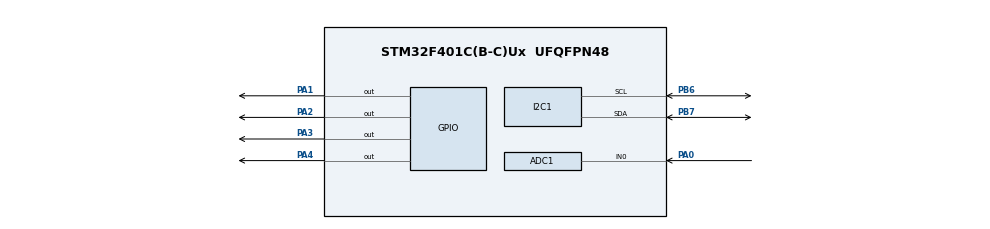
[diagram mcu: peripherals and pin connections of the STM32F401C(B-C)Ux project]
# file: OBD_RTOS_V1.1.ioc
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ADC1.Channel-0\#ChannelRegularConversion=ADC_CHANNEL_0
ADC1.NbrOfConversionFlag=1
ADC1.Rank-0\#ChannelRegularConversion=1
ADC1.SamplingTime-0\#ChannelRegularConversion=ADC_SAMPLETIME_3CYCLES
ADC1.master=1
FREERTOS.Tasks01=Tim_Task1,24,128,IncTimFunc,Default,NULL,Dynamic,NULL,NULL;TimTask2,8,128,EEPROM_saveTimVal,Default,NULL,Dynamic,NULL,NULL;fuelLevelTask1,8,128,getFuelLevelFromADC,Default,NULL,Dynamic,NULL,NULL;fuelLevelTask2,8,128,mapFuelLevelDigtalToLED,Default,NULL,Dynamic,NULL,NULL
Mcu.Family=STM32F4
Mcu.Name=STM32F401C(B-C)Ux
Mcu.Package=UFQFPN48
NVIC.PriorityGroup=NVIC_PRIORITYGROUP_4
PA0-WKUP.Signal=ADCx_IN0
PA1.Signal=GPIO_Output
PA2.Signal=GPIO_Output
PA3.Signal=GPIO_Output
PA4.Signal=GPIO_Output
PB6.Mode=I2C
PB6.Signal=I2C1_SCL
PB7.Mode=I2C
PB7.Signal=I2C1_SDA
ProjectManager.HeapSize=0x200
ProjectManager.StackSize=0x400
ProjectManager.TargetToolchain=STM32CubeIDE
RCC.48MHZClocksFreq_Value=36000000
RCC.AHBFreq_Value=72000000
RCC.APB1CLKDivider=RCC_HCLK_DIV2
RCC.APB1Freq_Value=36000000
RCC.APB1TimFreq_Value=72000000
RCC.APB2Freq_Value=72000000
RCC.APB2TimFreq_Value=72000000
RCC.CortexFreq_Value=72000000
RCC.HCLKFreq_Value=72000000
RCC.HSE_VALUE=25000000
RCC.HSI_VALUE=16000000
RCC.LSE_VALUE=32768
RCC.PLLM=8
RCC.PLLN=72
RCC.SYSCLKFreq_VALUE=72000000
RCC.SYSCLKSource=RCC_SYSCLKSOURCE_PLLCLK
RCC.VCOOutputFreq_Value=144000000
SH.ADCx_IN0.0=ADC1_IN0,IN0
VP_FREERTOS_VS_CMSIS_V2.Mode=CMSIS_V2
board=custom

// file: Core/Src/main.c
/* USER CODE BEGIN Header */
/**
 ******************************************************************************
 * @file           : main.c
 * @brief          : Main program body
 ******************************************************************************
 * @attention
 *
 * Copyright (c) 2023 STMicroelectronics.
 * All rights reserved.
 *
 * This software is licensed under terms that can be found in the LICENSE file
 * in the root directory of this software component.
 * If no LICENSE file comes with this software, it is provided AS-IS.
 *
 ******************************************************************************
 */
/* USER CODE END Header */
#include "main.h"
#include "cmsis_os.h"

/* USER CODE BEGIN Includes */
#include "EEPROM.h"
/* USER CODE END Includes */

/* USER CODE BEGIN PD */

//timer and eeprom
#define PAGE_NUM_TIM_LOC        1
#define PAGE_NUM_FLAG_LOC       100

#define OFFSET_NUM_TIM          1
#define OFFSET_NUM_FLAG         3

#define TIM_SIZE_DATA           4
#define FLAG_SIZE_DATA          1

#define FIRST_TIME             0xFF

//ADC and fuel level
#define FUEL_SENSOR_PIN				GPIO_PIN_0
#define FUEL_SENSOR_PORT			GPIOA

#define FUEL_LED0_PIN				GPIO_PIN_1
#define FUEL_LED0_PORT				GPIOA

#define FUEL_LED1_PIN				GPIO_PIN_2
#define FUEL_LED1_PORT				GPIOA

#define FUEL_LED2_PIN				GPIO_PIN_3
#define FUEL_LED2_PORT				GPIOA

#define FUEL_LED3_PIN				GPIO_PIN_4
#define FUEL_LED3_PORT				GPIOA

#define FUEL_MAX_DIGITA_VALUE		4096
#define FUEL_MINIMUM_DIGITA_VALUE	0

#define FUEL_LEVEL_FULL_TANK		4
#define FUEL_LEVEL_THREE_Q_TANK		3
#define FUEL_LEVEL_HALF_TANK		2
#define FUEL_LEVEL_QUARTER_TANK		1
#define FUEL_LEVEL_EMPTY_TANK		0
//lm35 temprature part
#define LM35_SENSOR_PIN				GPIO_PIN_5
#define LM35_SENSOR_PORT			GPIOA

#define LM35_MAX_DIGITA_VALUE		4096
#define LM35_MINIMUM_DIGITA_VALUE	0

#define LM35_MAX_TEMPRATURE			150
#define LM35_MINIMUM_TEMPRATURE		2

#define LM35_MAX_OUT_VOLt			1480 	//in mv
#define LM35_MINIMUM_OUT_VOLT		0

/* USER CODE END PD */

ADC_HandleTypeDef hadc1;

I2C_HandleTypeDef hi2c1;

/* Definitions for tim_Task1 */
osThreadId_t tim_Task1Handle;
const osThreadAttr_t tim_Task1_attributes = {
		.name = "tim_Task1",
		.stack_size = 128 * 4,
		.priority = (osPriority_t) osPriorityNormal,
};
/* Definitions for timTask2 */
osThreadId_t timTask2Handle;
const osThreadAttr_t timTask2_attributes = {
		.name = "timTask2",
		.stack_size = 128 * 4,
		.priority = (osPriority_t) osPriorityLow,
};
/* Definitions for fuelLevelTask1 */
osThreadId_t fuelLevelTask1Handle;
const osThreadAttr_t fuelLevelTask1_attributes = {
		.name = "fuelLevelTask1",
		.stack_size = 128 * 4,
		.priority = (osPriority_t) osPriorityLow,
};
/* Definitions for fuelLevelTask2 */
osThreadId_t fuelLevelTask2Handle;
const osThreadAttr_t fuelLevelTask2_attributes = {
		.name = "fuelLevelTask2",
		.stack_size = 128 * 4,
		.priority = (osPriority_t) osPriorityLow,
};
/* Definitions for LM35Task0 */
osThreadId_t LM35Task0Handle;
const osThreadAttr_t LM35Task0_attributes = {
		.name = "LM35Task0",
		.stack_size = 128 * 4,
		.priority = (osPriority_t) osPriorityLow,
};
/* USER CODE BEGIN PV */

//time and eeprom
uint32_t g_timeElapsedSec = 0;
uint8_t g_flag ;
uint8_t Done = 0x2;

// fuel level
uint32_t adcFuelValue ;
uint8_t curretFuelValue ;

// lm35 temprature
uint16_t ADC_TempratureDigitalRead ;
uint8_t  temperatureInCelsius ;
uint16_t  temperatureInMVolt ;

/* USER CODE END PV */

void SystemClock_Config(void);
static void MX_GPIO_Init(void);
static void MX_I2C1_Init(void);
static void MX_ADC1_Init(void);
void IncTimFunc(void *argument);
void EEPROM_saveTimVal(void *argument);
void getFuelLevelFromADC(void *argument);
void mapFuelLevelDigtalToLED(void *argument);
void LM35_getTemprature(void *argument);

/* USER CODE BEGIN PFP */

//time and eeprom
void EEPROM_voidInitTime(void);
uint32_t GetElapsedTime(void);

//fuel level
void mapDigitalvalueToLeds(uint32_t digitalValue);

//lm35 temprature

void getDigitalTemperatureFromADC ();
void mapDigitalTemperatureToVolt();
void mapMVoltToCelsius();

/* USER CODE END PFP */

int main(void)
{

	/* MCU Configuration--------------------------------------------------------*/

	/* Reset of all peripherals, Initializes the Flash interface and the Systick. */
	HAL_Init();

	/* Configure the system clock */
	SystemClock_Config();

	/* Initialize all configured peripherals */
	MX_GPIO_Init();
	MX_I2C1_Init();
	MX_ADC1_Init();
	/* USER CODE BEGIN 2 */
	HAL_I2C_Init(&hi2c1);
	EEPROM_voidInitTime();

	/* USER CODE END 2 */

	/* Init scheduler */
	osKernelInitialize();

	/* Create the thread(s) */
	/* creation of tim_Task1 */
	tim_Task1Handle = osThreadNew(IncTimFunc, NULL, &tim_Task1_attributes);

	/* creation of timTask2 */
	timTask2Handle = osThreadNew(EEPROM_saveTimVal, NULL, &timTask2_attributes);

	/* creation of fuelLevelTask1 */
	fuelLevelTask1Handle = osThreadNew(getFuelLevelFromADC, NULL, &fuelLevelTask1_attributes);

	/* creation of fuelLevelTask2 */
	fuelLevelTask2Handle = osThreadNew(mapFuelLevelDigtalToLED, NULL, &fuelLevelTask2_attributes);

	/* creation of LM35Task0 */
	LM35Task0Handle = osThreadNew(LM35_getTemprature, NULL, &LM35Task0_attributes);

	/* Start scheduler */
	osKernelStart();

	/* We should never get here as control is now taken by the scheduler */
	/* Infinite loop */
	while (1)
	{

	}
}

void SystemClock_Config(void)
{
	RCC_OscInitTypeDef RCC_OscInitStruct = {0};
	RCC_ClkInitTypeDef RCC_ClkInitStruct = {0};

	/** Configure the main internal regulator output voltage
	 */
	__HAL_RCC_PWR_CLK_ENABLE();
	__HAL_PWR_VOLTAGESCALING_CONFIG(PWR_REGULATOR_VOLTAGE_SCALE2);

	/** Initializes the RCC Oscillators according to the specified parameters
	 * in the RCC_OscInitTypeDef structure.
	 */
	RCC_OscInitStruct.OscillatorType = RCC_OSCILLATORTYPE_HSI;
	RCC_OscInitStruct.HSIState = RCC_HSI_ON;
	RCC_OscInitStruct.HSICalibrationValue = RCC_HSICALIBRATION_DEFAULT;
	RCC_OscInitStruct.PLL.PLLState = RCC_PLL_NONE;
	if (HAL_RCC_OscConfig(&RCC_OscInitStruct) != HAL_OK)
	{
		Error_Handler();
	}

	/** Initializes the CPU, AHB and APB buses clocks
	 */
	RCC_ClkInitStruct.ClockType = RCC_CLOCKTYPE_HCLK|RCC_CLOCKTYPE_SYSCLK
			|RCC_CLOCKTYPE_PCLK1|RCC_CLOCKTYPE_PCLK2;
	RCC_ClkInitStruct.SYSCLKSource = RCC_SYSCLKSOURCE_HSI;
	RCC_ClkInitStruct.AHBCLKDivider = RCC_SYSCLK_DIV1;
	RCC_ClkInitStruct.APB1CLKDivider = RCC_HCLK_DIV2;
	RCC_ClkInitStruct.APB2CLKDivider = RCC_HCLK_DIV1;

	if (HAL_RCC_ClockConfig(&RCC_ClkInitStruct, FLASH_LATENCY_0) != HAL_OK)
	{
		Error_Handler();
	}
}

static void MX_ADC1_Init(void)
{

	ADC_ChannelConfTypeDef sConfig = {0};

	/** Configure the global features of the ADC (Clock, Resolution, Data Alignment and number of conversion)
	 */
	hadc1.Instance = ADC1;
	hadc1.Init.ClockPrescaler = ADC_CLOCK_SYNC_PCLK_DIV2;
	hadc1.Init.Resolution = ADC_RESOLUTION_12B;
	hadc1.Init.ScanConvMode = DISABLE;
	hadc1.Init.ContinuousConvMode = DISABLE;
	hadc1.Init.DiscontinuousConvMode = DISABLE;
	hadc1.Init.ExternalTrigConvEdge = ADC_EXTERNALTRIGCONVEDGE_NONE;
	hadc1.Init.ExternalTrigConv = ADC_SOFTWARE_START;
	hadc1.Init.DataAlign = ADC_DATAALIGN_RIGHT;
	hadc1.Init.NbrOfConversion = 1;
	hadc1.Init.DMAContinuousRequests = DISABLE;
	hadc1.Init.EOCSelection = ADC_EOC_SINGLE_CONV;
	if (HAL_ADC_Init(&hadc1) != HAL_OK)
	{
		Error_Handler();
	}

	/** Configure for the selected ADC regular channel its corresponding rank in the sequencer and its sample time.
	 */
	sConfig.Channel = ADC_CHANNEL_0;
	sConfig.Rank = 1;
	sConfig.SamplingTime = ADC_SAMPLETIME_3CYCLES;
	if (HAL_ADC_ConfigChannel(&hadc1, &sConfig) != HAL_OK)
	{
		Error_Handler();
	}

}

static void MX_I2C1_Init(void)
{

	hi2c1.Instance = I2C1;
	hi2c1.Init.ClockSpeed = 100000;
	hi2c1.Init.DutyCycle = I2C_DUTYCYCLE_2;
	hi2c1.Init.OwnAddress1 = 0;
	hi2c1.Init.AddressingMode = I2C_ADDRESSINGMODE_7BIT;
	hi2c1.Init.DualAddressMode = I2C_DUALADDRESS_DISABLE;
	hi2c1.Init.OwnAddress2 = 0;
	hi2c1.Init.GeneralCallMode = I2C_GENERALCALL_DISABLE;
	hi2c1.Init.NoStretchMode = I2C_NOSTRETCH_DISABLE;
	if (HAL_I2C_Init(&hi2c1) != HAL_OK)
	{
		Error_Handler();
	}

}

static void MX_GPIO_Init(void)
{
	GPIO_InitTypeDef GPIO_InitStruct = {0};

	/* GPIO Ports Clock Enable */
	__HAL_RCC_GPIOA_CLK_ENABLE();
	__HAL_RCC_GPIOB_CLK_ENABLE();

	/*Configure GPIO pin Output Level */
	HAL_GPIO_WritePin(GPIOA, GPIO_PIN_1|GPIO_PIN_2|GPIO_PIN_3|GPIO_PIN_4, GPIO_PIN_RESET);

	/*Configure GPIO pins : PA1 PA2 PA3 PA4 */
	GPIO_InitStruct.Pin = GPIO_PIN_1|GPIO_PIN_2|GPIO_PIN_3|GPIO_PIN_4;
	GPIO_InitStruct.Mode = GPIO_MODE_OUTPUT_PP;
	GPIO_InitStruct.Pull = GPIO_NOPULL;
	GPIO_InitStruct.Speed = GPIO_SPEED_FREQ_LOW;
	HAL_GPIO_Init(GPIOA, &GPIO_InitStruct);

}

/* USER CODE BEGIN 4 */

//time and eeprom  no RTOS
uint32_t GetElapsedTime(void){
	uint32_t l_ElapsTim = g_timeElapsedSec;
	return l_ElapsTim;
}
/* Read Flag value */
void EEPROM_voidInitTime(void){
	EEPROM_Read(PAGE_NUM_FLAG_LOC, OFFSET_NUM_FLAG, &g_flag, FLAG_SIZE_DATA);

	HAL_Delay(5);
	if(g_flag != FIRST_TIME){

		EEPROM_Read(PAGE_NUM_TIM_LOC, OFFSET_NUM_TIM, (uint8_t *)&g_timeElapsedSec, TIM_SIZE_DATA);
	}
	else{
		/* It's First time */
		/* Erase our used loc in EEPROM to make sure that is clear */
		for(uint8_t i = 0 ; i < 7 ; i++){
			EEPROM_PageErase(i);
		}
		EEPROM_Write(PAGE_NUM_FLAG_LOC, OFFSET_NUM_FLAG,&Done, FLAG_SIZE_DATA);
	}
}

//fuel part no RTOS
void mapDigitalvalueToLeds(uint32_t digitalValue){
	//empty tank
	if (digitalValue <= FUEL_MINIMUM_DIGITA_VALUE){

		HAL_GPIO_WritePin(FUEL_LED0_PORT, FUEL_LED0_PIN,GPIO_PIN_SET);
		HAL_GPIO_WritePin(FUEL_LED1_PORT, FUEL_LED1_PIN,GPIO_PIN_SET);
		HAL_GPIO_WritePin(FUEL_LED2_PORT, FUEL_LED2_PIN,GPIO_PIN_SET);
		HAL_GPIO_WritePin(FUEL_LED3_PORT, FUEL_LED3_PIN,GPIO_PIN_SET);

		curretFuelValue = FUEL_LEVEL_EMPTY_TANK;
	}
	//quarter tank
	else if (digitalValue <= (FUEL_MAX_DIGITA_VALUE - FUEL_MINIMUM_DIGITA_VALUE)/4){

		HAL_GPIO_WritePin(FUEL_LED0_PORT, FUEL_LED0_PIN,GPIO_PIN_SET);
		HAL_GPIO_WritePin(FUEL_LED1_PORT, FUEL_LED1_PIN,GPIO_PIN_SET);
		HAL_GPIO_WritePin(FUEL_LED2_PORT, FUEL_LED2_PIN,GPIO_PIN_SET);
		HAL_GPIO_WritePin(FUEL_LED3_PORT, FUEL_LED3_PIN,GPIO_PIN_RESET);

		curretFuelValue = FUEL_LEVEL_QUARTER_TANK;
	}
	//Half tank
	else if (digitalValue <= (FUEL_MAX_DIGITA_VALUE - FUEL_MINIMUM_DIGITA_VALUE)/2){

		HAL_GPIO_WritePin(FUEL_LED0_PORT, FUEL_LED0_PIN,GPIO_PIN_SET);
		HAL_GPIO_WritePin(FUEL_LED1_PORT, FUEL_LED1_PIN,GPIO_PIN_SET);
		HAL_GPIO_WritePin(FUEL_LED2_PORT, FUEL_LED2_PIN,GPIO_PIN_RESET);
		HAL_GPIO_WritePin(FUEL_LED3_PORT, FUEL_LED3_PIN,GPIO_PIN_RESET);

		curretFuelValue = FUEL_LEVEL_HALF_TANK;
	}
	//3 quarters tank
	else if (digitalValue <= (FUEL_MAX_DIGITA_VALUE - FUEL_MINIMUM_DIGITA_VALUE)/4*3){

		HAL_GPIO_WritePin(FUEL_LED0_PORT, FUEL_LED0_PIN,GPIO_PIN_SET);
		HAL_GPIO_WritePin(FUEL_LED1_PORT, FUEL_LED1_PIN,GPIO_PIN_RESET);
		HAL_GPIO_WritePin(FUEL_LED2_PORT, FUEL_LED2_PIN,GPIO_PIN_RESET);
		HAL_GPIO_WritePin(FUEL_LED3_PORT, FUEL_LED3_PIN,GPIO_PIN_RESET);

		curretFuelValue = FUEL_LEVEL_THREE_Q_TANK;
	}
	//Full tank
	else if (digitalValue <= (FUEL_MAX_DIGITA_VALUE - FUEL_MINIMUM_DIGITA_VALUE)){

		HAL_GPIO_WritePin(FUEL_LED0_PORT, FUEL_LED0_PIN,GPIO_PIN_RESET);
		HAL_GPIO_WritePin(FUEL_LED1_PORT, FUEL_LED1_PIN,GPIO_PIN_RESET);
		HAL_GPIO_WritePin(FUEL_LED2_PORT, FUEL_LED2_PIN,GPIO_PIN_RESET);
		HAL_GPIO_WritePin(FUEL_LED3_PORT, FUEL_LED3_PIN,GPIO_PIN_RESET);

		curretFuelValue = FUEL_LEVEL_FULL_TANK;
	}
}

//lm 35 temprater no RTOS
void getDigitalTemperatureFromADC (){
	HAL_ADC_Start(&hadc1);
	HAL_ADC_PollForConversion(&hadc1, 100);
	ADC_TempratureDigitalRead = HAL_ADC_GetValue(&hadc1);
	HAL_ADC_Stop(&hadc1);
}
void mapDigitalTemperatureToVolt() {
	temperatureInMVolt = (ADC_TempratureDigitalRead*(LM35_MAX_OUT_VOLt-LM35_MINIMUM_OUT_VOLT))/(LM35_MAX_DIGITA_VALUE)+LM35_MINIMUM_OUT_VOLT;
}

void mapMVoltToCelsius() {
	temperatureInCelsius = (temperatureInMVolt*(LM35_MAX_TEMPRATURE-LM35_MINIMUM_TEMPRATURE))/(LM35_MAX_OUT_VOLt-LM35_MINIMUM_OUT_VOLT) + LM35_MINIMUM_TEMPRATURE ;
}

/* USER CODE END 4 */

void IncTimFunc(void *argument)
{
	/* USER CODE BEGIN 5 */
	/* Infinite loop */
	for(;;)
	{
		g_timeElapsedSec += 2;

		osDelay(2000);
	}
	/* USER CODE END 5 */
}

void EEPROM_saveTimVal(void *argument)
{
	/* USER CODE BEGIN EEPROM_saveTimVal */
	/* Infinite loop */
	for(;;)
	{
		EEPROM_Write(PAGE_NUM_TIM_LOC, OFFSET_NUM_TIM,(uint8_t *)&g_timeElapsedSec,TIM_SIZE_DATA);

		osDelay(10000);
	}
	/* USER CODE END EEPROM_saveTimVal */
}

void getFuelLevelFromADC(void *argument)
{
	/* USER CODE BEGIN getFuelLevelFromADC */
	osDelay(500);
	/* Infinite loop */
	for(;;)
	{
		HAL_ADC_Start(&hadc1);
		HAL_ADC_PollForConversion(&hadc1, 100);
		adcFuelValue = HAL_ADC_GetValue(&hadc1);
		HAL_ADC_Stop(&hadc1);
		osDelay(2000);
	}
	/* USER CODE END getFuelLevelFromADC */
}

void mapFuelLevelDigtalToLED(void *argument)
{
	/* USER CODE BEGIN mapFuelLevelDigtalToLED */
	osDelay(550);

	/* Infinite loop */

	for(;;)
	{
		mapDigitalvalueToLeds(adcFuelValue);
		osDelay(2000);
	}
	/* USER CODE END mapFuelLevelDigtalToLED */
}

void LM35_getTemprature(void *argument)
{
	/* USER CODE BEGIN LM35_getTemprature */
	/* Infinite loop */
	for(;;)
	{
		//getting temperature digital value from adc
		getDigitalTemperatureFromADC();
		//mapping Digital temperature to volt
		mapDigitalTemperatureToVolt();
		//mapping volt to celsius
		mapMVoltToCelsius();

		// maping temp to 3 digits
		//uint8_t temp0 = (temperatureInCelsius%10 ) 		+ 48;
		//uint8_t temp1 = (temperatureInCelsius%100) /10 	+ 48;
		//uint8_t temp2 = (temperatureInCelsius/100) 		+ 48;

		osDelay(1000);
	}
	/* USER CODE END LM35_getTemprature */
}

void Error_Handler(void)
{
	__disable_irq();
	while (1)
	{
	}
}
